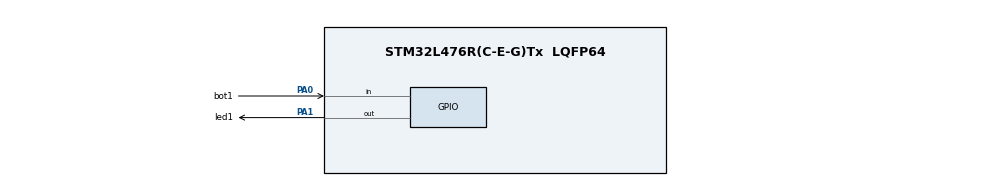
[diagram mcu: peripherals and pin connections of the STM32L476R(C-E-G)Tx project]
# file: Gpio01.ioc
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Mcu.Family=STM32L4
Mcu.Name=STM32L476R(C-E-G)Tx
Mcu.Package=LQFP64
NVIC.PriorityGroup=NVIC_PRIORITYGROUP_4
PA0.GPIO_Label=bot1
PA0.Signal=GPIO_Input
PA1.GPIO_Label=led1
PA1.Signal=GPIO_Output
ProjectManager.HeapSize=0x200
ProjectManager.StackSize=0x400
ProjectManager.TargetToolchain=STM32CubeIDE
RCC.ADCFreq_Value=64000000
RCC.AHBFreq_Value=80000000
RCC.APB1Freq_Value=80000000
RCC.APB1TimFreq_Value=80000000
RCC.APB2Freq_Value=80000000
RCC.APB2TimFreq_Value=80000000
RCC.CortexFreq_Value=80000000
RCC.HCLKFreq_Value=80000000
RCC.HSE_VALUE=8000000
RCC.HSI_VALUE=16000000
RCC.MSI_VALUE=4000000
RCC.PLLN=10
RCC.PLLSourceVirtual=RCC_PLLSOURCE_HSI
RCC.PREFETCH_ENABLE=1
RCC.SYSCLKFreq_VALUE=80000000
RCC.SYSCLKSource=RCC_SYSCLKSOURCE_PLLCLK
RCC.USBFreq_Value=64000000
RCC.VCOOutputFreq_Value=160000000
board=NUCLEO-L476RG

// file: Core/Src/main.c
/* USER CODE BEGIN Header */
/**
  ******************************************************************************
  * @file           : main.c
  * @brief          : Main program body
  ******************************************************************************
  * @attention
  *
  * Copyright (c) 2025 STMicroelectronics.
  * All rights reserved.
  *
  * This software is licensed under terms that can be found in the LICENSE file
  * in the root directory of this software component.
  * If no LICENSE file comes with this software, it is provided AS-IS.
  *
  ******************************************************************************
  */
/* USER CODE END Header */
#include "main.h"

void SystemClock_Config(void);
static void MX_GPIO_Init(void);

int main(void)
{

  /* MCU Configuration--------------------------------------------------------*/

  /* Reset of all peripherals, Initializes the Flash interface and the Systick. */
  HAL_Init();

  /* Configure the system clock */
  SystemClock_Config();

  /* Initialize all configured peripherals */
  MX_GPIO_Init();

  /* Infinite loop */
  while (1)
  {

    /* USER CODE BEGIN 3 */
	  // Se o botão B1 (PC13) for pressionado (nível lógico 0), o led LD2 (PA5) acende.
	  uint8_t value_button = HAL_GPIO_ReadPin(GPIOC, button1_Pin);
	  if (!value_button) {
		  HAL_GPIO_WritePin(GPIOA, led1_Pin, 1);
	}else{
		HAL_GPIO_WritePin(GPIOA, led1_Pin, 0);
	}

  }
  /* USER CODE END 3 */
}

void SystemClock_Config(void)
{
  RCC_OscInitTypeDef RCC_OscInitStruct = {0};
  RCC_ClkInitTypeDef RCC_ClkInitStruct = {0};

  /** Configure the main internal regulator output voltage
  */
  if (HAL_PWREx_ControlVoltageScaling(PWR_REGULATOR_VOLTAGE_SCALE1) != HAL_OK)
  {
    Error_Handler();
  }

  /** Initializes the RCC Oscillators according to the specified parameters
  * in the RCC_OscInitTypeDef structure.
  */
  RCC_OscInitStruct.OscillatorType = RCC_OSCILLATORTYPE_HSI;
  RCC_OscInitStruct.HSIState = RCC_HSI_ON;
  RCC_OscInitStruct.HSICalibrationValue = RCC_HSICALIBRATION_DEFAULT;
  RCC_OscInitStruct.PLL.PLLState = RCC_PLL_NONE;
  if (HAL_RCC_OscConfig(&RCC_OscInitStruct) != HAL_OK)
  {
    Error_Handler();
  }

  /** Initializes the CPU, AHB and APB buses clocks
  */
  RCC_ClkInitStruct.ClockType = RCC_CLOCKTYPE_HCLK|RCC_CLOCKTYPE_SYSCLK
                              |RCC_CLOCKTYPE_PCLK1|RCC_CLOCKTYPE_PCLK2;
  RCC_ClkInitStruct.SYSCLKSource = RCC_SYSCLKSOURCE_HSI;
  RCC_ClkInitStruct.AHBCLKDivider = RCC_SYSCLK_DIV1;
  RCC_ClkInitStruct.APB1CLKDivider = RCC_HCLK_DIV1;
  RCC_ClkInitStruct.APB2CLKDivider = RCC_HCLK_DIV1;

  if (HAL_RCC_ClockConfig(&RCC_ClkInitStruct, FLASH_LATENCY_0) != HAL_OK)
  {
    Error_Handler();
  }
}

static void MX_GPIO_Init(void)
{
  GPIO_InitTypeDef GPIO_InitStruct = {0};

  /* GPIO Ports Clock Enable */
  __HAL_RCC_GPIOC_CLK_ENABLE();
  __HAL_RCC_GPIOA_CLK_ENABLE();

  /*Configure GPIO pin Output Level */
  HAL_GPIO_WritePin(led1_GPIO_Port, led1_Pin, GPIO_PIN_RESET);

  /*Configure GPIO pin : button1_Pin */
  GPIO_InitStruct.Pin = button1_Pin;
  GPIO_InitStruct.Mode = GPIO_MODE_INPUT;
  GPIO_InitStruct.Pull = GPIO_NOPULL;
  HAL_GPIO_Init(button1_GPIO_Port, &GPIO_InitStruct);

  /*Configure GPIO pin : led1_Pin */
  GPIO_InitStruct.Pin = led1_Pin;
  GPIO_InitStruct.Mode = GPIO_MODE_OUTPUT_PP;
  GPIO_InitStruct.Pull = GPIO_NOPULL;
  GPIO_InitStruct.Speed = GPIO_SPEED_FREQ_LOW;
  HAL_GPIO_Init(led1_GPIO_Port, &GPIO_InitStruct);

}

void Error_Handler(void)
{
  __disable_irq();
  while (1)
  {
  }
}
